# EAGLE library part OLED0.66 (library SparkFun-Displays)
Micro OLED TODO: Add description SparkFun Products: Micro OLED Breakout

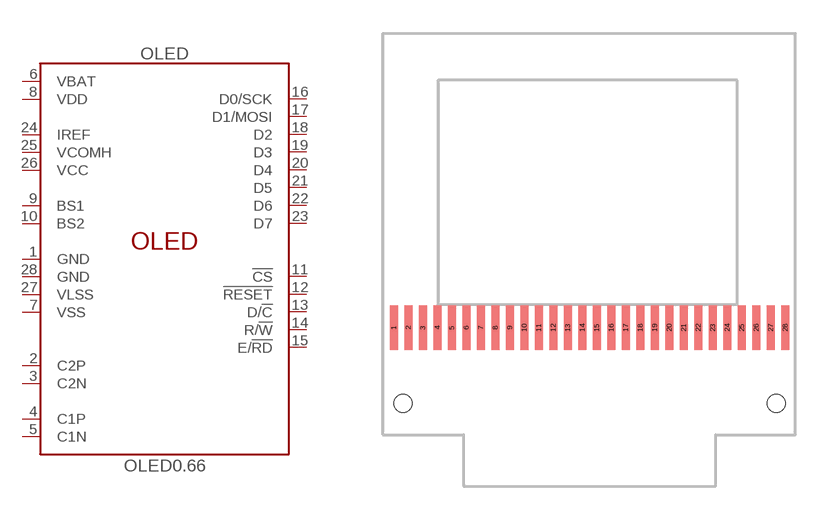
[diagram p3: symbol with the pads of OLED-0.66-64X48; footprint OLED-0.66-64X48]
Designator prefix OLED

## OLED0.66 (PROD_ID: LCD-12019)  [OLED-0.66-64X48]
1  GND
2  C2P
3  C2N
4  C1P
5  C1N
6  VBAT
7  VSS
8  VDD
9  BS1
10  BS2
11  !CS!
12  !RESET!
13  D/!C!
14  R/!W!
15  E/!RD!
16  D0/SCK
17  D1/MOSI
18  D2
19  D3
20  D4
21  D5
22  D6
23  D7
24  IREF
25  VCOMH
26  VCC
27  VLSS
28  GND

## Footprint OLED-0.66-64X48 (pad centres in mm)
OLDE display, 0.66 inch For MicroView. Specifications: Pin count: 28 Pin pitch: Area: Datasheet referenced for footprint: Example device(s): Microview breakout
smd 0.35 x 2: 1 -8.775,0; 2 -8.125,0; 3 -7.475,0; 4 -6.825,0; 5 -6.175,0; 6 -5.525,0; 7 -4.875,0; 8 -4.225,0; 9 -3.575,0; 10 -2.925,0; 11 -2.275,0; 12 -1.625,0; 13 -0.975,0; 14 -0.325,0; 15 0.325,0; 16 0.975,0; 17 1.625,0; 18 2.275,0; 19 2.925,0; 20 3.575,0; 21 4.225,0; 22 4.875,0; 23 5.525,0; 24 6.175,0; 25 6.825,0; 26 7.475,0; 27 8.125,0; 28 8.775,0
hole 0.8 at 8.375,-3.4
hole 0.8 at -8.375,-3.4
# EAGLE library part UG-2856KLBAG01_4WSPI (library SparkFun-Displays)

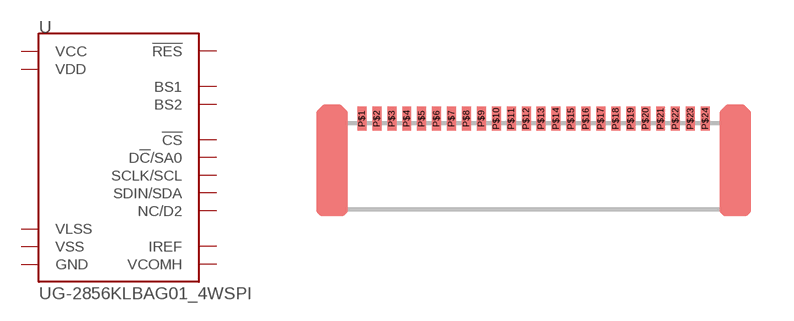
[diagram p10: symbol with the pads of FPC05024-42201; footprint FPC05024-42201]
Designator prefix U

## UG-2856KLBAG01_4WSPI (PROD_ID: CONN-14195)  [FPC05024-42201]
P$1  GND
P$2  VLSS
P$3  VSS
P$5  VDD
P$6  BS1
P$7  BS2
P$8  !CS
P$9  !RES
P$10  D!C!/SA0
P$11  GND
P$12  GND
P$13  SCLK/SCL
P$14  SDIN/SDA
P$15  NC/D2
P$16  GND
P$17  GND
P$18  GND
P$19  GND
P$20  GND
P$21  IREF
P$22  VCOMH
P$23  VCC
P$24  GND

## Footprint FPC05024-42201 (pad centres in mm)
SparkFun SKU CONN-14195
smd 0.3 x 0.8: P$1 -5.75,0.4; P$2 -5.25,0.4; P$3 -4.75,0.4; P$4 -4.25,0.4; P$5 -3.75,0.4; P$6 -3.25,0.4; P$7 -2.75,0.4; P$8 -2.25,0.4; P$9 -1.75,0.4; P$10 -1.25,0.4; P$11 -0.75,0.4; P$12 -0.25,0.4; P$13 0.25,0.4; P$14 0.75,0.4; P$15 1.25,0.4; P$16 1.75,0.4; P$17 2.25,0.4; P$18 2.75,0.4; P$19 3.25,0.4; P$20 3.75,0.4; P$21 4.25,0.4; P$22 4.75,0.4; P$23 5.25,0.4; P$24 5.75,0.4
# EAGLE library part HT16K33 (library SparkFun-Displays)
HT16K33 24 SOP-A : RAM Mapping 16x8 LED Controller Driver with Keyscan

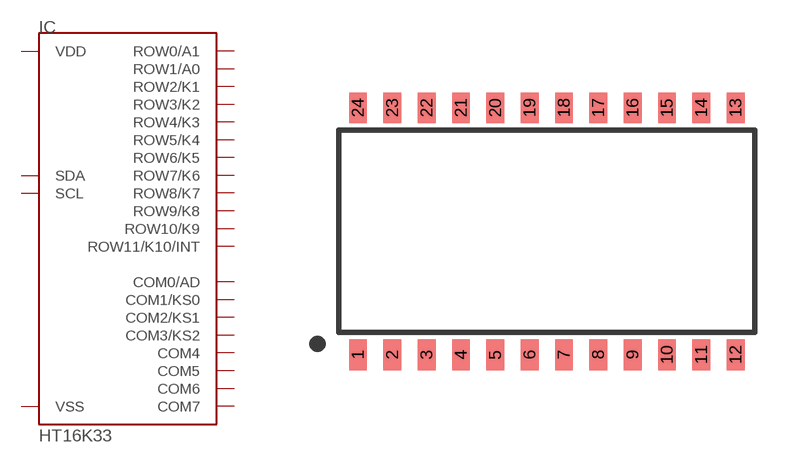
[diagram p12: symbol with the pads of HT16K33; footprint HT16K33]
Designator prefix IC

## HT16K33 (PROD_ID: IC-14891; VALUE: HTK16K33)  [HT16K33]
1  VSS
2  COM0/AD
3  COM1/KS0
4  COM2/KS1
5  COM3/KS2
6  COM4
7  COM5
8  COM6
9  COM7
10  ROW11/K10/INT
11  ROW10/K9
12  ROW9/K8
13  ROW8/K7
14  ROW7/K6
15  ROW6/K5
16  ROW5/K4
17  ROW4/K3
18  ROW3/K2
19  ROW2/K1
20  ROW1/A0
21  ROW0/A1
22  SCL
23  SDA
24  VDD  pwr

## Footprint HT16K33 (pad centres in mm)
smd 0.66 x 1.143: 1 -6.985,-4.572; 2 -5.715,-4.572; 3 -4.445,-4.572; 4 -3.175,-4.572; 5 -1.905,-4.572; 6 -0.635,-4.572; 7 0.635,-4.572; 8 1.905,-4.572; 9 3.175,-4.572; 10 4.445,-4.572; 11 5.715,-4.572; 12 6.985,-4.572; 13 6.985,4.572; 14 5.715,4.572; 15 4.445,4.572; 16 3.175,4.572; 17 1.905,4.572; 18 0.635,4.572; 19 -0.635,4.572; 20 -1.905,4.572; 21 -3.175,4.572; 22 -4.445,4.572; 23 -5.715,4.572; 24 -6.985,4.572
